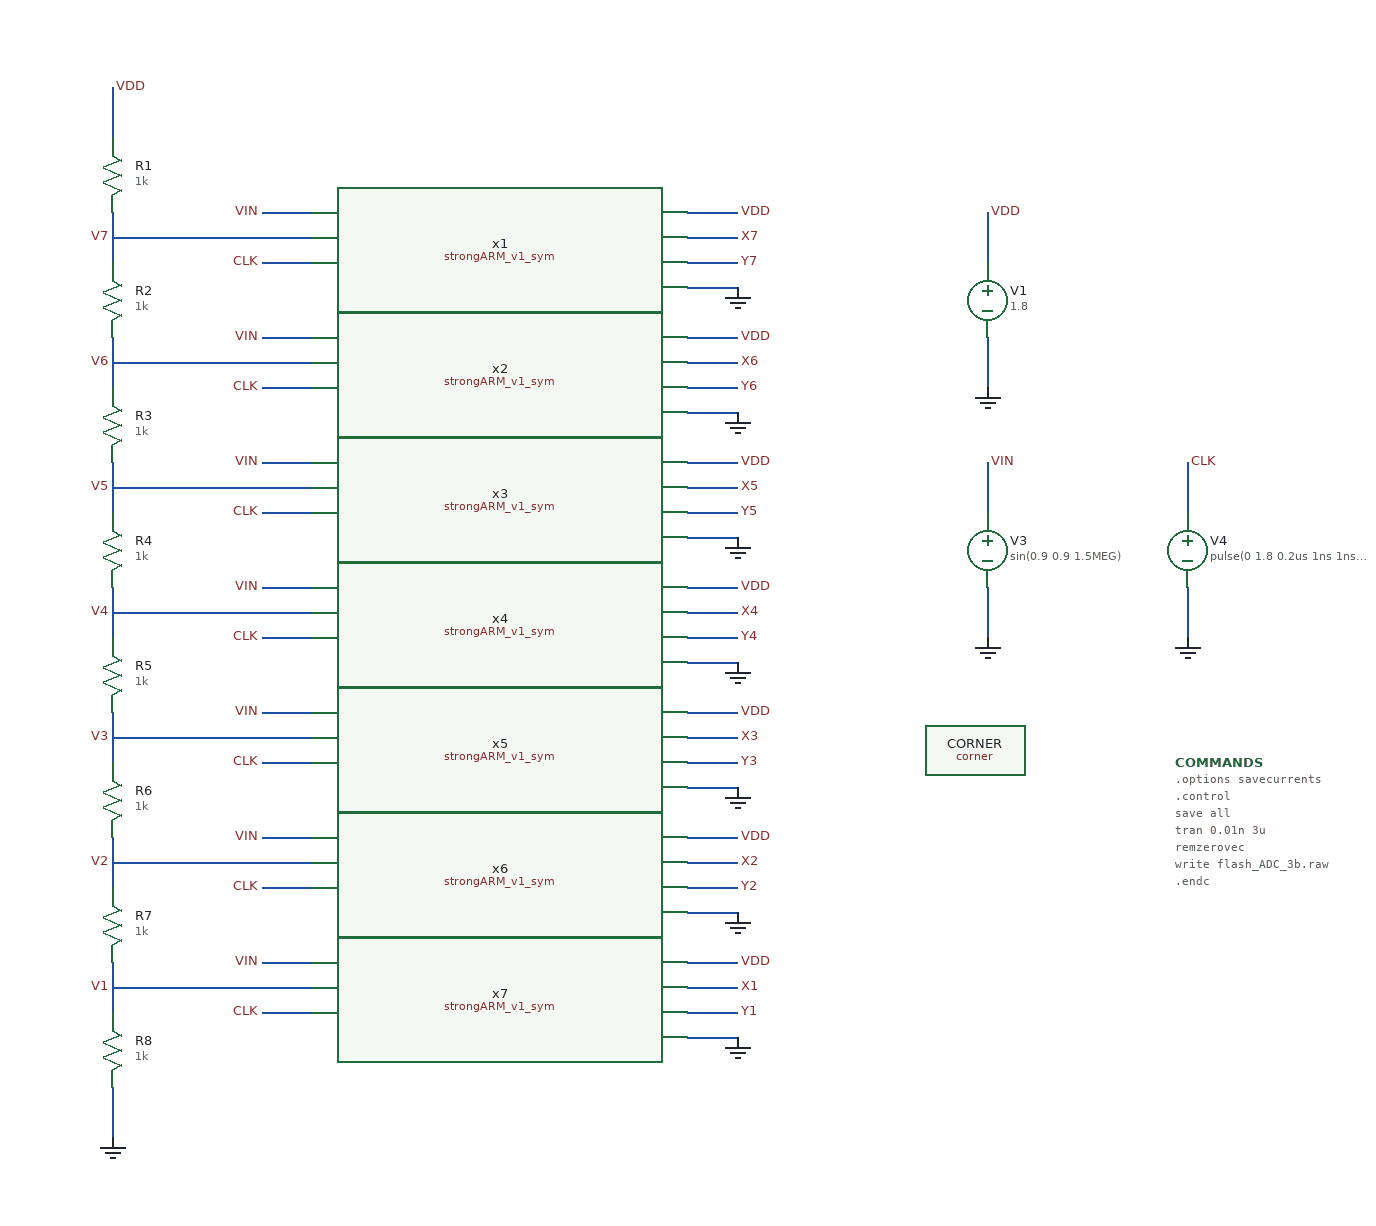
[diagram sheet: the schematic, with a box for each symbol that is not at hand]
v {xschem version=3.4.5 file_version=1.2
}
G {}
K {}
V {}
S {}
E {}
B 2 1320 -400 2120 0 {flags=graph
y1=0
y2=2
ypos1=0
ypos2=2
divy=5
subdivy=1
unity=1
x1=0
x2=3e-06
divx=5
subdivx=1
xlabmag=1.0
ylabmag=1.0


dataset=-1
unitx=1
logx=0
logy=0
color=4
node=clk}
B 2 1320 -800 2120 -400 {flags=graph
y1=1.1e-10
y2=2.1
ypos1=0
ypos2=2
divy=5
subdivy=1
unity=1
x1=0
x2=3e-06
divx=5
subdivx=1
xlabmag=1.0
ylabmag=1.0


dataset=-1
unitx=1
logx=0
logy=0
color="4 5 6"
node="y1
v1
vin"}
B 2 1320 -1200 2120 -800 {flags=graph
y1=1.1e-10
y2=2.1
ypos1=0
ypos2=2
divy=5
subdivy=1
unity=1
x1=0
x2=3e-06
divx=5
subdivx=1
xlabmag=1.0
ylabmag=1.0


dataset=-1
unitx=1
logx=0
logy=0




color="4 5 6"
node="y2
v2
vin"}
B 2 1320 -1600 2120 -1200 {flags=graph
y1=-0.068
y2=2.1
ypos1=0
ypos2=2
divy=5
subdivy=1
unity=1
x1=0
x2=3e-06
divx=5
subdivx=1
xlabmag=1.0
ylabmag=1.0


dataset=-1
unitx=1
logx=0
logy=0
color="4 5 6"
node="y3
v3
vin"}
B 2 1320 -2000 2120 -1600 {flags=graph
y1=-0.066
y2=2.1
ypos1=0
ypos2=2
divy=5
subdivy=1
unity=1
x1=0
x2=3e-06
divx=5
subdivx=1
xlabmag=1.0
ylabmag=1.0
node="y4
v4
vin"
color="4 5 6"
dataset=-1
unitx=1
logx=0
logy=0
}
B 2 1320 -2400 2120 -2000 {flags=graph
y1=-0.065
y2=2.1
ypos1=0
ypos2=2
divy=5
subdivy=1
unity=1
x1=0
x2=3e-06
divx=5
subdivx=1
xlabmag=1.0
ylabmag=1.0


dataset=-1
unitx=1
logx=0
logy=0

color="4 5 6"
node="y5
v5
vin"}
B 2 1320 -2800 2120 -2400 {flags=graph
y1=-0.064
y2=2.1
ypos1=0
ypos2=2
divy=5
subdivy=1
unity=1
x1=0
x2=3e-06
divx=5
subdivx=1
xlabmag=1.0
ylabmag=1.0
node="y6
v6
vin"
color="4 5 6"
dataset=-1
unitx=1
logx=0
logy=0
}
B 2 1320 -3200 2120 -2800 {flags=graph
y1=-0.063
y2=2
ypos1=0
ypos2=2
divy=5
subdivy=1
unity=1
x1=0
x2=3e-06
divx=5
subdivx=1
xlabmag=1.0
ylabmag=1.0


dataset=-1
unitx=1
logx=0
logy=0
color="4 5 6"
node="y7
v7
vin"}
N 180 -1320 180 -1280 {
lab=VDD}
N 180 -1220 180 -1180 {
lab=V7}
N 180 -1120 180 -1080 {
lab=V6}
N 180 -1020 180 -980 {
lab=V5}
N 180 -920 180 -880 {
lab=V4}
N 180 -820 180 -780 {
lab=V3}
N 180 -720 180 -680 {
lab=V2}
N 180 -620 180 -580 {
lab=V1}
N 180 -520 180 -480 {
lab=GND}
N 180 -1200 240 -1200 {
lab=V7}
N 180 -1100 240 -1100 {
lab=V6}
N 240 -1200 340 -1200 {
lab=V7}
N 240 -1100 340 -1100 {
lab=V6}
N 180 -1000 340 -1000 {
lab=V5}
N 180 -900 340 -900 {
lab=V4}
N 180 -800 340 -800 {
lab=V3}
N 180 -700 340 -700 {
lab=V2}
N 180 -600 340 -600 {
lab=V1}
N 300 -1220 340 -1220 {
lab=VIN}
N 300 -1120 340 -1120 {
lab=VIN}
N 300 -1080 340 -1080 {
lab=CLK}
N 300 -1020 340 -1020 {
lab=VIN}
N 300 -980 340 -980 {
lab=CLK}
N 300 -920 340 -920 {
lab=VIN}
N 300 -820 340 -820 {
lab=VIN}
N 300 -720 340 -720 {
lab=VIN}
N 300 -620 340 -620 {
lab=VIN}
N 300 -580 340 -580 {
lab=CLK}
N 640 -1220 680 -1220 {
lab=VDD}
N 640 -1200 680 -1200 {
lab=X7}
N 640 -1180 680 -1180 {
lab=Y7}
N 640 -1160 680 -1160 {
lab=GND}
N 640 -1120 680 -1120 {
lab=VDD}
N 640 -1100 680 -1100 {
lab=X6}
N 640 -1080 680 -1080 {
lab=Y6}
N 640 -1060 680 -1060 {
lab=GND}
N 640 -1020 680 -1020 {
lab=VDD}
N 640 -1000 680 -1000 {
lab=X5}
N 640 -980 680 -980 {
lab=Y5}
N 640 -960 680 -960 {
lab=GND}
N 640 -920 680 -920 {
lab=VDD}
N 640 -900 680 -900 {
lab=X4}
N 640 -880 680 -880 {
lab=Y4}
N 640 -860 680 -860 {
lab=GND}
N 640 -820 680 -820 {
lab=VDD}
N 640 -800 680 -800 {
lab=X3}
N 640 -780 670 -780 {
lab=Y3}
N 670 -780 680 -780 {
lab=Y3}
N 640 -760 680 -760 {
lab=GND}
N 640 -720 680 -720 {
lab=VDD}
N 640 -700 680 -700 {
lab=X2}
N 640 -680 680 -680 {
lab=Y2}
N 640 -660 680 -660 {
lab=GND}
N 640 -620 680 -620 {
lab=VDD}
N 640 -600 680 -600 {
lab=X1}
N 640 -580 680 -580 {
lab=Y1}
N 640 -560 680 -560 {
lab=GND}
N 310 -880 340 -880 {
lab=CLK}
N 300 -880 310 -880 {
lab=CLK}
N 300 -780 340 -780 {
lab=CLK}
N 300 -680 340 -680 {
lab=CLK}
N 300 -1180 340 -1180 {
lab=CLK}
N 880 -1220 880 -1180 {
lab=VDD}
N 880 -1120 880 -1080 {
lab=GND}
N 880 -1020 880 -980 {
lab=VIN}
N 880 -920 880 -880 {
lab=GND}
N 1040 -1020 1040 -980 {
lab=CLK}
N 1040 -920 1040 -880 {
lab=GND}
C {/foss/designs/Analog_FA23_SP24/strongARM/strongARM_v1_sym.sym} 490 -1190 0 0 {name=x1}
C {devices/res.sym} 180 -1250 0 0 {name=R1
value=1k
footprint=1206
device=resistor
m=1}
C {devices/res.sym} 180 -1150 0 0 {name=R2
value=1k
footprint=1206
device=resistor
m=1}
C {devices/res.sym} 180 -1050 0 0 {name=R3
value=1k
footprint=1206
device=resistor
m=1}
C {devices/res.sym} 180 -950 0 0 {name=R4
value=1k
footprint=1206
device=resistor
m=1}
C {devices/res.sym} 180 -850 0 0 {name=R5
value=1k
footprint=1206
device=resistor
m=1}
C {devices/res.sym} 180 -750 0 0 {name=R6
value=1k
footprint=1206
device=resistor
m=1}
C {devices/res.sym} 180 -650 0 0 {name=R7
value=1k
footprint=1206
device=resistor
m=1}
C {devices/res.sym} 180 -550 0 0 {name=R8
value=1k
footprint=1206
device=resistor
m=1}
C {devices/lab_pin.sym} 180 -1320 2 0 {name=p1 sig_type=std_logic lab=VDD}
C {devices/gnd.sym} 180 -480 0 0 {name=l1 lab=GND}
C {/foss/designs/Analog_FA23_SP24/strongARM/strongARM_v1_sym.sym} 490 -1090 0 0 {name=x2}
C {/foss/designs/Analog_FA23_SP24/strongARM/strongARM_v1_sym.sym} 490 -990 0 0 {name=x3}
C {/foss/designs/Analog_FA23_SP24/strongARM/strongARM_v1_sym.sym} 490 -890 0 0 {name=x4}
C {/foss/designs/Analog_FA23_SP24/strongARM/strongARM_v1_sym.sym} 490 -790 0 0 {name=x5}
C {/foss/designs/Analog_FA23_SP24/strongARM/strongARM_v1_sym.sym} 490 -690 0 0 {name=x6}
C {/foss/designs/Analog_FA23_SP24/strongARM/strongARM_v1_sym.sym} 490 -590 0 0 {name=x7}
C {devices/gnd.sym} 680 -1160 0 0 {name=l2 lab=GND}
C {devices/gnd.sym} 680 -1060 0 0 {name=l3 lab=GND}
C {devices/gnd.sym} 680 -960 0 0 {name=l4 lab=GND}
C {devices/gnd.sym} 680 -860 0 0 {name=l5 lab=GND}
C {devices/gnd.sym} 680 -760 0 0 {name=l6 lab=GND}
C {devices/gnd.sym} 680 -660 0 0 {name=l7 lab=GND}
C {devices/gnd.sym} 680 -560 0 0 {name=l8 lab=GND}
C {devices/lab_pin.sym} 300 -1180 0 0 {name=p6 sig_type=std_logic lab=CLK}
C {devices/lab_pin.sym} 300 -1080 0 0 {name=p2 sig_type=std_logic lab=CLK}
C {devices/lab_pin.sym} 300 -980 0 0 {name=p3 sig_type=std_logic lab=CLK}
C {devices/lab_pin.sym} 300 -880 0 0 {name=p4 sig_type=std_logic lab=CLK}
C {devices/lab_pin.sym} 300 -780 0 0 {name=p5 sig_type=std_logic lab=CLK}
C {devices/lab_pin.sym} 300 -680 0 0 {name=p7 sig_type=std_logic lab=CLK}
C {devices/lab_pin.sym} 300 -580 0 0 {name=p8 sig_type=std_logic lab=CLK}
C {devices/lab_pin.sym} 300 -1220 0 0 {name=p9 sig_type=std_logic lab=VIN}
C {devices/lab_pin.sym} 300 -1120 0 0 {name=p10 sig_type=std_logic lab=VIN}
C {devices/lab_pin.sym} 300 -1020 0 0 {name=p11 sig_type=std_logic lab=VIN}
C {devices/lab_pin.sym} 300 -920 0 0 {name=p12 sig_type=std_logic lab=VIN}
C {devices/lab_pin.sym} 300 -820 0 0 {name=p13 sig_type=std_logic lab=VIN}
C {devices/lab_pin.sym} 300 -720 0 0 {name=p14 sig_type=std_logic lab=VIN}
C {devices/lab_pin.sym} 300 -620 0 0 {name=p15 sig_type=std_logic lab=VIN}
C {devices/lab_pin.sym} 680 -1220 2 0 {name=p16 sig_type=std_logic lab=VDD}
C {devices/lab_pin.sym} 680 -1120 2 0 {name=p17 sig_type=std_logic lab=VDD}
C {devices/lab_pin.sym} 680 -1020 2 0 {name=p18 sig_type=std_logic lab=VDD}
C {devices/lab_pin.sym} 680 -920 2 0 {name=p19 sig_type=std_logic lab=VDD}
C {devices/lab_pin.sym} 680 -820 2 0 {name=p20 sig_type=std_logic lab=VDD}
C {devices/lab_pin.sym} 680 -720 2 0 {name=p21 sig_type=std_logic lab=VDD}
C {devices/lab_pin.sym} 680 -620 2 0 {name=p22 sig_type=std_logic lab=VDD}
C {devices/lab_pin.sym} 680 -600 2 0 {name=p23 sig_type=std_logic lab=X1}
C {devices/lab_pin.sym} 680 -580 2 0 {name=p24 sig_type=std_logic lab=Y1}
C {devices/lab_pin.sym} 680 -680 2 0 {name=p25 sig_type=std_logic lab=Y2}
C {devices/lab_pin.sym} 680 -700 2 0 {name=p26 sig_type=std_logic lab=X2}
C {devices/lab_pin.sym} 680 -780 2 0 {name=p27 sig_type=std_logic lab=Y3}
C {devices/lab_pin.sym} 680 -800 2 0 {name=p28 sig_type=std_logic lab=X3}
C {devices/lab_pin.sym} 680 -880 2 0 {name=p29 sig_type=std_logic lab=Y4}
C {devices/lab_pin.sym} 680 -900 2 0 {name=p30 sig_type=std_logic lab=X4}
C {devices/lab_pin.sym} 680 -1000 2 0 {name=p31 sig_type=std_logic lab=X5}
C {devices/lab_pin.sym} 680 -980 2 0 {name=p32 sig_type=std_logic lab=Y5}
C {devices/lab_pin.sym} 680 -1100 2 0 {name=p33 sig_type=std_logic lab=X6
}
C {devices/lab_pin.sym} 680 -1080 2 0 {name=p34 sig_type=std_logic lab=Y6}
C {devices/lab_pin.sym} 680 -1200 2 0 {name=p35 sig_type=std_logic lab=X7
}
C {devices/lab_pin.sym} 680 -1180 2 0 {name=p36 sig_type=std_logic lab=Y7}
C {devices/vsource.sym} 880 -1150 0 0 {name=V1 value=1.8 savecurrent=false}
C {devices/gnd.sym} 880 -1080 0 0 {name=l9 lab=GND}
C {devices/lab_pin.sym} 880 -1220 2 0 {name=p37 sig_type=std_logic lab=VDD}
C {devices/vsource.sym} 880 -950 0 0 {name=V3 value="sin(0.9 0.9 1.5MEG)" savecurrent=false}
C {devices/gnd.sym} 880 -880 0 0 {name=l10 lab=GND}
C {devices/lab_pin.sym} 880 -1020 2 0 {name=p38 sig_type=std_logic lab=VIN}
C {devices/vsource.sym} 1040 -950 0 0 {name=V4 value="pulse(0 1.8 0.2us 1ns 1ns 0.5us 1us)" savecurrent=false}
C {devices/gnd.sym} 1040 -880 0 0 {name=l11 lab=GND}
C {devices/lab_pin.sym} 1040 -1020 2 0 {name=p39 sig_type=std_logic lab=CLK}
C {sky130_fd_pr/corner.sym} 870 -790 0 0 {name=CORNER only_toplevel=false corner=tt}
C {devices/code_shown.sym} 1030 -780 0 0 {name=COMMANDS only_toplevel=false value=
"
.options savecurrents
.control

save all

tran 0.01n 3u
remzerovec
write flash_ADC_3b.raw

.endc
"}
C {devices/lab_pin.sym} 180 -1200 0 0 {name=p40 sig_type=std_logic lab=V7
}
C {devices/lab_pin.sym} 180 -1100 0 0 {name=p41 sig_type=std_logic lab=V6
}
C {devices/lab_pin.sym} 180 -1000 0 0 {name=p42 sig_type=std_logic lab=V5
}
C {devices/lab_pin.sym} 180 -900 0 0 {name=p43 sig_type=std_logic lab=V4
}
C {devices/lab_pin.sym} 180 -800 0 0 {name=p44 sig_type=std_logic lab=V3
}
C {devices/lab_pin.sym} 180 -700 0 0 {name=p45 sig_type=std_logic lab=V2
}
C {devices/lab_pin.sym} 180 -600 0 0 {name=p46 sig_type=std_logic lab=V1
}
